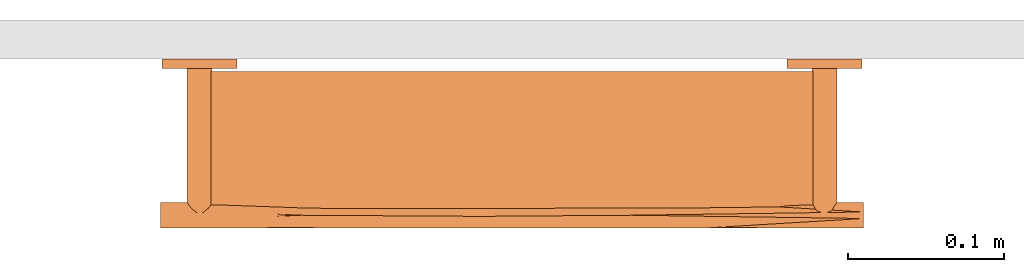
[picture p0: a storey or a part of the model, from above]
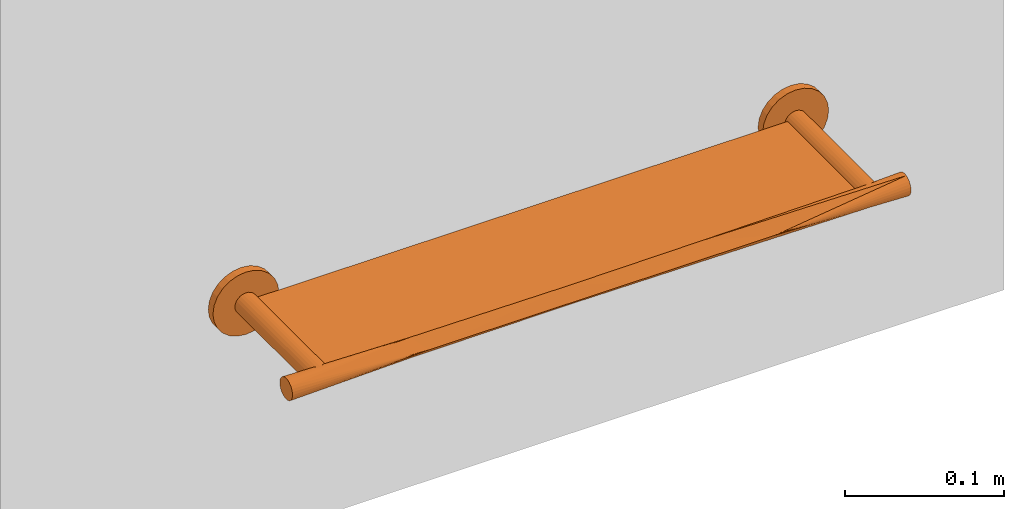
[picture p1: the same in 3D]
Properties of the parts of a building model (IFC2X3)

# File
Description: ViewDefinition [CoordinationView]
Time: 2016-08-02T14:24:55
Written by: The EXPRESS Data Manager Version 5.01.0100.02.64mod : 6 Jun 2012
Made in: 20140709_2115(x64) - Exporter 2014.0.2014.0709 - Default UI
Comment: STEP Physical File produced by: The EXPRESS Data Manager Version 5.01.0100.02.64mod : 6 Jun 2012 * Module: EDMstepFileFactory/EDMstandAlone * Creation date: Tue Aug 02 14:24:55 2016 * Host: BIM-HP * Database: C:\Users\dcole\AppData\Local\Temp\{8B3F5BB2-9DAC-493A-B817-3F48B39E224D}\ifc * Database version: 5507 * Database creation date: Tue Aug 02 14:24:52 2016 * Schema: IFC2X3 * Model: DataRepository.ifc * Model creation date: Tue Aug 02 14:24:53 2016 * Header model: DataRepository.ifc_HeaderModel * Header model creation date: Tue Aug 02 14:24:53 2016 * EDMuser: sdai-user * EDMgroup: sdai-group * License ID and type: 5605 : Permanent license. Expiry date: * EDMstepFileFactory options: 020000

# IfcProject
LongName: P:\Fastrack\53721_BELL-CHEM\ADDITIONAL DRAWINGS 2016 BIM\IFC\BC729.ifc

# IfcSite, Default
RefLatitude: 42, 24, 53, 508911; RefLongitude: -71, -15, -29, -58837; RefElevation: 0 mm

# IfcBuilding
Pset_BuildingCommon - NumberOfStoreys: 1

# IfcBuildingStorey, Level 1
LongName: Level 1; Elevation: 0 mm
Constraints - Elevation Base: Project Base Point; Elevation: 0 mm
Dimensions - Computation Height: 0 mm
Identity Data - Building Story: yes; Name: Level 1; Structural: no
Graphics - Color: 0; Line Weight: 1; Symbol at End 1 Default: no; Line Pattern: -3000010; Symbol at End 2 Default: yes

# IfcBuildingElementProxy: BC729 Dolphin Glass Shelf, BC729:BC729 Dolphin Glass Shelf:35295
In: Level 1
Material: Glass
Other - Schedule Level: Level: Level 1
Phasing - Phase Created: New Construction
Constraints - Work Plane: Basic Wall : Wall 1; Offset: 0 mm; Default Elevation: 0 mm
Dimensions - Volume: 0.000410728 m3; Width: 450mm; Height: 48mm; Projection: 108mm
Pset_ManufacturerTypeInformation - Manufacturer: Bell-Chem Products Ltd
Pset_BuildingElementProxyCommon - Reference: BC729 Dolphin Glass Shelf
Identity Data - Assembly Code: D2010900; Tel No.: +44 (0) 1424 202 224; Model: BC729; Assembly Description: Other Plumbing Fixtures; Address: Southpoint, Compass Park, Bodiam, Robertsbridge, TN32 5BS; URL: www.dolphinsolutions.co.uk; Manufacturer: Bell-Chem Products Ltd; Fax No.: +44 (0) 1424 205 200; Email: info@dolphinsolutions.co.uk; Description: Glass shelf
General - Product Page Link: https://www.dolphinsolutions.co.uk/product/glass-shelf/; Product Data: Timeless design for prestigious appearance in high class environments. 304 stainless steel for easy care and durability. Robust 'hidden fix' anti-rotation wall plate fixing for secure anti-theft mounting. Available in satin (brushed) stainless steel to compliment other Dolphin products. Robust 7mm tempered glass shelf for safety and durability, transparent finish.

# IfcWallStandardCase: Basic Wall:Wall 1, Basic Wall:Wall 1:3092
In: Level 1
Type - PredefinedType: STANDARD; Material: Default Wall 25 mm
Type - Graphics - Coarse Scale Fill Color: 8454143
Type - Construction - Wrapping at Inserts: Do not wrap; Function: Exterior; Width: 25 mm
Type - Analytical Properties - Roughness: 1; Absorptance: 0.1
Dimensions - Volume: 0.0093826 m3; Area: 0.375304 m2; Length: 730 mm
Structural - Enable Analytical Model: no; Structural Usage: Non-bearing; Structural: no
Constraints - Related to Mass: no; Unconnected Height: 514.115 mm; Top Extension Distance: 0 mm; Top Offset: 0 mm; Base Constraint: Level: Level 1; Top is Attached: no; Room Bounding: yes; Location Line: Finish Face: Interior; Base Extension Distance: 0 mm; Base is Attached: no; Base Offset: -247.742 mm
Phasing - Phase Created: New Construction
Pset_WallCommon - Reference: Wall 1; LoadBearing: no; ExtendToStructure: no; IsExternal: yes
